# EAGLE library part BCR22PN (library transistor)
NPN/PNP Silicon Digital Transistor Array Source: Infineon-BCR22PN-DS-v01_01-en.pdf

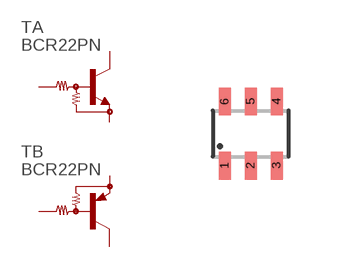
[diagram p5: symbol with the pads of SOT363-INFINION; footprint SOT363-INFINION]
Designator prefix T; gates A=NPN-DRIVER B=PNP-DRIVER

## BCR22PN  [SOT363-INFINION]
1  A:E  pas
2  A:B  pas
3  B:C  pas
4  B:E  pas
5  B:B  pas
6  A:C  pas

## Footprint SOT363-INFINION (pad centres in mm)
SOT363 Source: Infineon-BCR22PN-DS-v01_01-en.pdf
smd 0.3 x 0.7: 1 -0.65,-0.8; 2 0,-0.8; 3 0.65,-0.8; 4 0.65,0.8; 5 0,0.8; 6 -0.65,0.8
